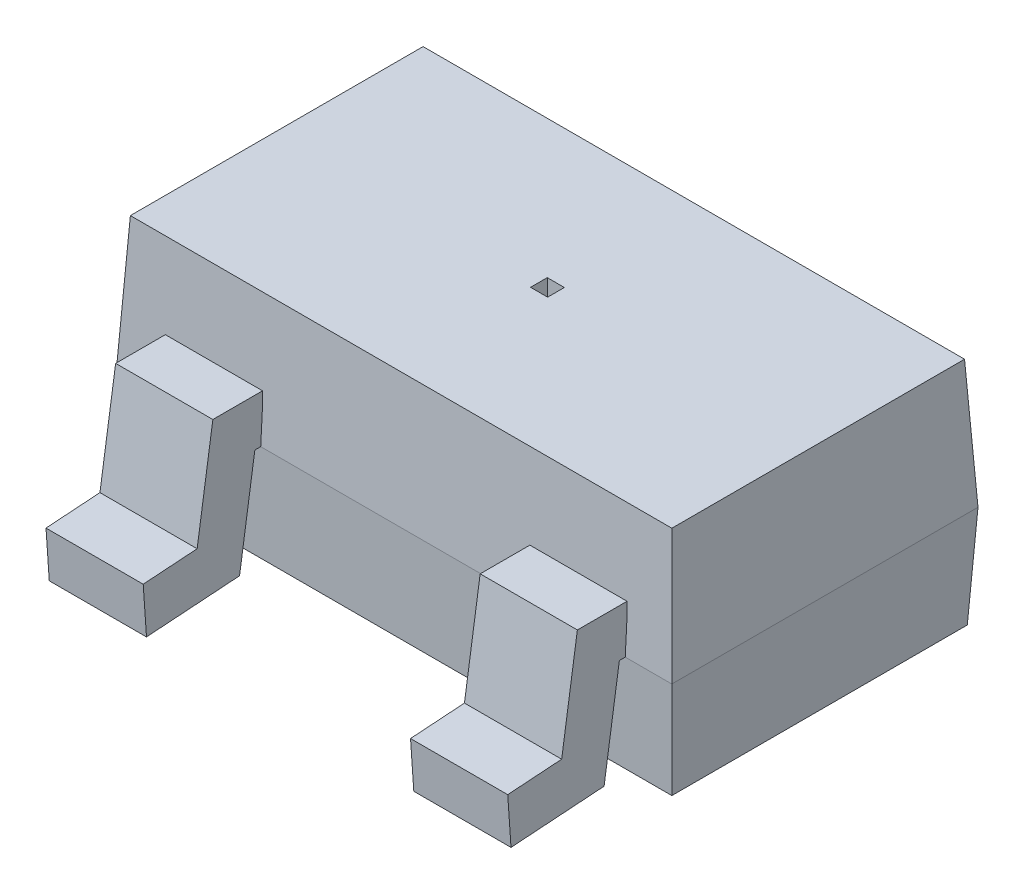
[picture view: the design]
ISO-10303-21;
HEADER;
FILE_DESCRIPTION(('STEP AP214'),'2;1');
FILE_NAME('part.step','',(''),(''),'','','');
FILE_SCHEMA(('AUTOMOTIVE_DESIGN { 1 0 10303 214 1 1 1 1 }'));
ENDSEC;
DATA;
#1=APPLICATION_CONTEXT('core data for automotive mechanical design processes');
#2=APPLICATION_PROTOCOL_DEFINITION('international standard','automotive_design',2000,#1);
#3=PRODUCT_CONTEXT('',#1,'mechanical');
#4=PRODUCT('Part','Part','',(#3));
#5=PRODUCT_RELATED_PRODUCT_CATEGORY('part','',(#4));
#6=PRODUCT_DEFINITION_FORMATION('','',#4);
#7=PRODUCT_DEFINITION_CONTEXT('part definition',#1,'design');
#8=PRODUCT_DEFINITION('design','',#6,#7);
#9=PRODUCT_DEFINITION_SHAPE('','',#8);
#10=(LENGTH_UNIT() NAMED_UNIT(*) SI_UNIT(.MILLI.,.METRE.));
#11=(NAMED_UNIT(*) PLANE_ANGLE_UNIT() SI_UNIT($,.RADIAN.));
#12=(NAMED_UNIT(*) SI_UNIT($,.STERADIAN.) SOLID_ANGLE_UNIT());
#13=UNCERTAINTY_MEASURE_WITH_UNIT(LENGTH_MEASURE(1.E-05),#10,'distance_accuracy_value','');
#14=(GEOMETRIC_REPRESENTATION_CONTEXT(3) GLOBAL_UNCERTAINTY_ASSIGNED_CONTEXT((#13)) GLOBAL_UNIT_ASSIGNED_CONTEXT((#10,
#11,#12)) REPRESENTATION_CONTEXT('',''));
#15=CARTESIAN_POINT('',(0.,0.,0.));
#16=DIRECTION('',(0.,0.,1.));
#17=DIRECTION('',(1.,0.,0.));
#18=AXIS2_PLACEMENT_3D('',#15,#16,#17);
#19=CARTESIAN_POINT('',(-1.45,0.,-0.8));
#20=DIRECTION('',(-0.998629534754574,-0.0523359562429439,0.));
#21=DIRECTION('',(0.0523359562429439,-0.998629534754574,0.));
#22=AXIS2_PLACEMENT_3D('',#19,#20,#21);
#23=PLANE('',#22);
#24=DIRECTION('',(0.,0.,1.));
#25=VECTOR('',#24,1.);
#26=CARTESIAN_POINT('',(-1.45,0.,-0.8));
#27=LINE('',#26,#25);
#28=CARTESIAN_POINT('',(-1.45,0.,-0.8));
#29=VERTEX_POINT('',#28);
#30=CARTESIAN_POINT('',(-1.45,0.,0.8));
#31=VERTEX_POINT('',#30);
#32=EDGE_CURVE('E491',#29,#31,#27,.T.);
#33=ORIENTED_EDGE('',*,*,#32,.F.);
#34=DIRECTION('',(-0.052264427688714,0.997264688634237,-0.052264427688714));
#35=VECTOR('',#34,1.);
#36=CARTESIAN_POINT('',(-1.45,0.,-0.8));
#37=LINE('',#36,#35);
#38=CARTESIAN_POINT('',(-1.42206665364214,-0.533,-0.772066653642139));
#39=VERTEX_POINT('',#38);
#40=EDGE_CURVE('E526',#39,#29,#37,.T.);
#41=ORIENTED_EDGE('',*,*,#40,.F.);
#42=DIRECTION('',(0.,0.,1.));
#43=VECTOR('',#42,1.);
#44=CARTESIAN_POINT('',(-1.42206665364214,-0.533,0.8));
#45=LINE('',#44,#43);
#46=CARTESIAN_POINT('',(-1.42206665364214,-0.533,0.772066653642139));
#47=VERTEX_POINT('',#46);
#48=EDGE_CURVE('E524',#39,#47,#45,.T.);
#49=ORIENTED_EDGE('',*,*,#48,.T.);
#50=DIRECTION('',(-0.052264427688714,0.997264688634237,0.052264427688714));
#51=VECTOR('',#50,1.);
#52=CARTESIAN_POINT('',(-1.44562948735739,-0.0833943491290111,0.795629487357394));
#53=LINE('',#52,#51);
#54=EDGE_CURVE('E531',#47,#31,#53,.T.);
#55=ORIENTED_EDGE('',*,*,#54,.T.);
#56=EDGE_LOOP('',(#33,#41,#49,#55));
#57=FACE_BOUND('',#56,.T.);
#58=ADVANCED_FACE('F38',(#57),#23,.T.);
#59=CARTESIAN_POINT('',(-1.45,0.,-0.8));
#60=DIRECTION('',(0.,-0.0523359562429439,-0.998629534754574));
#61=DIRECTION('',(0.,0.998629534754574,-0.0523359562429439));
#62=AXIS2_PLACEMENT_3D('',#59,#60,#61);
#63=PLANE('',#62);
#64=DIRECTION('',(-1.,0.,0.));
#65=VECTOR('',#64,1.);
#66=CARTESIAN_POINT('',(-1.45,0.,-0.8));
#67=LINE('',#66,#65);
#68=CARTESIAN_POINT('',(1.45,0.,-0.8));
#69=VERTEX_POINT('',#68);
#70=CARTESIAN_POINT('',(0.254,0.,-0.8));
#71=VERTEX_POINT('',#70);
#72=EDGE_CURVE('E521',#69,#71,#67,.T.);
#73=ORIENTED_EDGE('',*,*,#72,.F.);
#74=DIRECTION('',(0.052264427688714,0.997264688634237,-0.052264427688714));
#75=VECTOR('',#74,1.);
#76=CARTESIAN_POINT('',(1.45,0.,-0.8));
#77=LINE('',#76,#75);
#78=CARTESIAN_POINT('',(1.42206665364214,-0.533,-0.772066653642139));
#79=VERTEX_POINT('',#78);
#80=EDGE_CURVE('E530',#79,#69,#77,.T.);
#81=ORIENTED_EDGE('',*,*,#80,.F.);
#82=DIRECTION('',(-1.,0.,0.));
#83=VECTOR('',#82,1.);
#84=CARTESIAN_POINT('',(-1.45,-0.533,-0.772066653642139));
#85=LINE('',#84,#83);
#86=EDGE_CURVE('E534',#79,#39,#85,.T.);
#87=ORIENTED_EDGE('',*,*,#86,.T.);
#88=ORIENTED_EDGE('',*,*,#40,.T.);
#89=CARTESIAN_POINT('',(-0.254,0.,-0.8));
#90=VERTEX_POINT('',#89);
#91=EDGE_CURVE('E520',#90,#29,#67,.T.);
#92=ORIENTED_EDGE('',*,*,#91,.F.);
#93=EDGE_CURVE('E525',#71,#90,#67,.T.);
#94=ORIENTED_EDGE('',*,*,#93,.F.);
#95=EDGE_LOOP('',(#73,#81,#87,#88,#92,#94));
#96=FACE_BOUND('',#95,.T.);
#97=ADVANCED_FACE('F40',(#96),#63,.T.);
#98=CARTESIAN_POINT('',(1.45,0.,-0.8));
#99=DIRECTION('',(0.998629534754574,-0.0523359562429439,0.));
#100=DIRECTION('',(0.0523359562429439,0.998629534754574,0.));
#101=AXIS2_PLACEMENT_3D('',#98,#99,#100);
#102=PLANE('',#101);
#103=DIRECTION('',(0.,0.,-1.));
#104=VECTOR('',#103,1.);
#105=CARTESIAN_POINT('',(1.45,0.,-0.8));
#106=LINE('',#105,#104);
#107=CARTESIAN_POINT('',(1.45,0.,0.8));
#108=VERTEX_POINT('',#107);
#109=EDGE_CURVE('E514',#108,#69,#106,.T.);
#110=ORIENTED_EDGE('',*,*,#109,.F.);
#111=DIRECTION('',(0.052264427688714,0.997264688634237,0.052264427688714));
#112=VECTOR('',#111,1.);
#113=CARTESIAN_POINT('',(1.44207844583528,-0.151152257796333,0.792078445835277));
#114=LINE('',#113,#112);
#115=CARTESIAN_POINT('',(1.42206665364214,-0.533,0.772066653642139));
#116=VERTEX_POINT('',#115);
#117=EDGE_CURVE('E533',#116,#108,#114,.T.);
#118=ORIENTED_EDGE('',*,*,#117,.F.);
#119=DIRECTION('',(0.,0.,-1.));
#120=VECTOR('',#119,1.);
#121=CARTESIAN_POINT('',(1.42206665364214,-0.533,0.8));
#122=LINE('',#121,#120);
#123=EDGE_CURVE('E543',#116,#79,#122,.T.);
#124=ORIENTED_EDGE('',*,*,#123,.T.);
#125=ORIENTED_EDGE('',*,*,#80,.T.);
#126=EDGE_LOOP('',(#110,#118,#124,#125));
#127=FACE_BOUND('',#126,.T.);
#128=ADVANCED_FACE('F665',(#127),#102,.T.);
#129=CARTESIAN_POINT('',(-1.45,0.,0.8));
#130=DIRECTION('',(0.,-0.0523359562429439,0.998629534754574));
#131=DIRECTION('',(0.,-0.998629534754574,-0.0523359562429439));
#132=AXIS2_PLACEMENT_3D('',#129,#130,#131);
#133=PLANE('',#132);
#134=DIRECTION('',(1.,0.,0.));
#135=VECTOR('',#134,1.);
#136=CARTESIAN_POINT('',(-1.45,0.,0.8));
#137=LINE('',#136,#135);
#138=CARTESIAN_POINT('',(-1.2065,0.,0.8));
#139=VERTEX_POINT('',#138);
#140=EDGE_CURVE('E512',#31,#139,#137,.T.);
#141=ORIENTED_EDGE('',*,*,#140,.F.);
#142=ORIENTED_EDGE('',*,*,#54,.F.);
#143=DIRECTION('',(1.,0.,0.));
#144=VECTOR('',#143,1.);
#145=CARTESIAN_POINT('',(-1.45,-0.533,0.772066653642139));
#146=LINE('',#145,#144);
#147=EDGE_CURVE('E540',#47,#116,#146,.T.);
#148=ORIENTED_EDGE('',*,*,#147,.T.);
#149=ORIENTED_EDGE('',*,*,#117,.T.);
#150=CARTESIAN_POINT('',(1.2065,0.,0.8));
#151=VERTEX_POINT('',#150);
#152=EDGE_CURVE('E511',#151,#108,#137,.T.);
#153=ORIENTED_EDGE('',*,*,#152,.F.);
#154=CARTESIAN_POINT('',(0.6985,0.,0.8));
#155=VERTEX_POINT('',#154);
#156=EDGE_CURVE('E517',#155,#151,#137,.T.);
#157=ORIENTED_EDGE('',*,*,#156,.F.);
#158=CARTESIAN_POINT('',(-0.6985,0.,0.8));
#159=VERTEX_POINT('',#158);
#160=EDGE_CURVE('E516',#159,#155,#137,.T.);
#161=ORIENTED_EDGE('',*,*,#160,.F.);
#162=EDGE_CURVE('E515',#139,#159,#137,.T.);
#163=ORIENTED_EDGE('',*,*,#162,.F.);
#164=EDGE_LOOP('',(#141,#142,#148,#149,#153,#157,#161,#163));
#165=FACE_BOUND('',#164,.T.);
#166=ADVANCED_FACE('F672',(#165),#133,.T.);
#167=CARTESIAN_POINT('',(-1.45,-0.533,0.8));
#168=DIRECTION('',(0.,1.,0.));
#169=DIRECTION('',(0.,0.,1.));
#170=AXIS2_PLACEMENT_3D('',#167,#168,#169);
#171=PLANE('',#170);
#172=ORIENTED_EDGE('',*,*,#48,.F.);
#173=ORIENTED_EDGE('',*,*,#86,.F.);
#174=ORIENTED_EDGE('',*,*,#123,.F.);
#175=ORIENTED_EDGE('',*,*,#147,.F.);
#176=EDGE_LOOP('',(#172,#173,#174,#175));
#177=FACE_BOUND('',#176,.T.);
#178=ADVANCED_FACE('F670',(#177),#171,.F.);
#179=CARTESIAN_POINT('',(1.45,0.,-0.8));
#180=DIRECTION('',(0.,0.0523359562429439,-0.998629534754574));
#181=DIRECTION('',(0.,0.998629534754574,0.0523359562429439));
#182=AXIS2_PLACEMENT_3D('',#179,#180,#181);
#183=PLANE('',#182);
#184=ORIENTED_EDGE('',*,*,#72,.T.);
#185=DIRECTION('',(0.,-0.998629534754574,-0.0523359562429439));
#186=VECTOR('',#185,1.);
#187=CARTESIAN_POINT('',(0.254,0.,-0.8));
#188=LINE('',#187,#186);
#189=CARTESIAN_POINT('',(0.254,0.18203300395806,-0.790460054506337));
#190=VERTEX_POINT('',#189);
#191=EDGE_CURVE('E553',#71,#190,#188,.F.);
#192=ORIENTED_EDGE('',*,*,#191,.T.);
#193=DIRECTION('',(-1.,0.,0.));
#194=VECTOR('',#193,1.);
#195=CARTESIAN_POINT('',(1.45,0.18203300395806,-0.790460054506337));
#196=LINE('',#195,#194);
#197=CARTESIAN_POINT('',(-0.254,0.182033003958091,-0.790460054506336));
#198=VERTEX_POINT('',#197);
#199=EDGE_CURVE('E550',#198,#190,#196,.F.);
#200=ORIENTED_EDGE('',*,*,#199,.F.);
#201=DIRECTION('',(0.,-0.998629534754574,-0.0523359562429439));
#202=VECTOR('',#201,1.);
#203=CARTESIAN_POINT('',(-0.254,0.,-0.8));
#204=LINE('',#203,#202);
#205=EDGE_CURVE('E529',#90,#198,#204,.F.);
#206=ORIENTED_EDGE('',*,*,#205,.F.);
#207=ORIENTED_EDGE('',*,*,#91,.T.);
#208=DIRECTION('',(-0.052264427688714,-0.997264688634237,-0.052264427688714));
#209=VECTOR('',#208,1.);
#210=CARTESIAN_POINT('',(-1.45,0.,-0.8));
#211=LINE('',#210,#209);
#212=CARTESIAN_POINT('',(-1.41488678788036,0.67,-0.764886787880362));
#213=VERTEX_POINT('',#212);
#214=EDGE_CURVE('E488',#213,#29,#211,.T.);
#215=ORIENTED_EDGE('',*,*,#214,.F.);
#216=DIRECTION('',(1.,0.,0.));
#217=VECTOR('',#216,1.);
#218=CARTESIAN_POINT('',(1.45,0.67,-0.764886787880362));
#219=LINE('',#218,#217);
#220=CARTESIAN_POINT('',(1.41488678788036,0.67,-0.764886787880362));
#221=VERTEX_POINT('',#220);
#222=EDGE_CURVE('E487',#221,#213,#219,.F.);
#223=ORIENTED_EDGE('',*,*,#222,.F.);
#224=DIRECTION('',(0.052264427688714,-0.997264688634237,-0.052264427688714));
#225=VECTOR('',#224,1.);
#226=CARTESIAN_POINT('',(1.45,0.,-0.8));
#227=LINE('',#226,#225);
#228=EDGE_CURVE('E493',#221,#69,#227,.T.);
#229=ORIENTED_EDGE('',*,*,#228,.T.);
#230=EDGE_LOOP('',(#184,#192,#200,#206,#207,#215,#223,#229));
#231=FACE_BOUND('',#230,.T.);
#232=ADVANCED_FACE('F777',(#231),#183,.T.);
#233=CARTESIAN_POINT('',(-1.45,0.,-0.8));
#234=DIRECTION('',(-0.998629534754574,0.0523359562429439,0.));
#235=DIRECTION('',(-0.0523359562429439,-0.998629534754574,0.));
#236=AXIS2_PLACEMENT_3D('',#233,#234,#235);
#237=PLANE('',#236);
#238=ORIENTED_EDGE('',*,*,#32,.T.);
#239=DIRECTION('',(-0.052264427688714,-0.997264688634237,0.052264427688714));
#240=VECTOR('',#239,1.);
#241=CARTESIAN_POINT('',(-1.45,0.,0.8));
#242=LINE('',#241,#240);
#243=CARTESIAN_POINT('',(-1.41488678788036,0.67,0.764886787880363));
#244=VERTEX_POINT('',#243);
#245=EDGE_CURVE('E492',#244,#31,#242,.T.);
#246=ORIENTED_EDGE('',*,*,#245,.F.);
#247=DIRECTION('',(0.,0.,-1.));
#248=VECTOR('',#247,1.);
#249=CARTESIAN_POINT('',(-1.41488678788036,0.67,-0.8));
#250=LINE('',#249,#248);
#251=EDGE_CURVE('E504',#213,#244,#250,.F.);
#252=ORIENTED_EDGE('',*,*,#251,.F.);
#253=ORIENTED_EDGE('',*,*,#214,.T.);
#254=EDGE_LOOP('',(#238,#246,#252,#253));
#255=FACE_BOUND('',#254,.T.);
#256=ADVANCED_FACE('F692',(#255),#237,.T.);
#257=CARTESIAN_POINT('',(-1.45,0.,0.8));
#258=DIRECTION('',(0.,0.0523359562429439,0.998629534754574));
#259=DIRECTION('',(0.,-0.998629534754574,0.0523359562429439));
#260=AXIS2_PLACEMENT_3D('',#257,#258,#259);
#261=PLANE('',#260);
#262=ORIENTED_EDGE('',*,*,#140,.T.);
#263=DIRECTION('',(0.,-0.998629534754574,0.0523359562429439));
#264=VECTOR('',#263,1.);
#265=CARTESIAN_POINT('',(-1.2065,0.,0.8));
#266=LINE('',#265,#264);
#267=CARTESIAN_POINT('',(-1.2065,0.182033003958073,0.790460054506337));
#268=VERTEX_POINT('',#267);
#269=EDGE_CURVE('E11',#139,#268,#266,.F.);
#270=ORIENTED_EDGE('',*,*,#269,.T.);
#271=DIRECTION('',(-1.,0.,0.));
#272=VECTOR('',#271,1.);
#273=CARTESIAN_POINT('',(-1.45,0.182033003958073,0.790460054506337));
#274=LINE('',#273,#272);
#275=CARTESIAN_POINT('',(-0.6985,0.182033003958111,0.790460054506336));
#276=VERTEX_POINT('',#275);
#277=EDGE_CURVE('E46',#268,#276,#274,.F.);
#278=ORIENTED_EDGE('',*,*,#277,.T.);
#279=DIRECTION('',(0.,-0.998629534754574,0.0523359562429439));
#280=VECTOR('',#279,1.);
#281=CARTESIAN_POINT('',(-0.6985,0.,0.8));
#282=LINE('',#281,#280);
#283=EDGE_CURVE('E563',#159,#276,#282,.F.);
#284=ORIENTED_EDGE('',*,*,#283,.F.);
#285=ORIENTED_EDGE('',*,*,#160,.T.);
#286=DIRECTION('',(0.,0.998629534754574,-0.0523359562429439));
#287=VECTOR('',#286,1.);
#288=CARTESIAN_POINT('',(0.6985,0.,0.8));
#289=LINE('',#288,#287);
#290=CARTESIAN_POINT('',(0.6985,0.182033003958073,0.790460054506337));
#291=VERTEX_POINT('',#290);
#292=EDGE_CURVE('E555',#291,#155,#289,.F.);
#293=ORIENTED_EDGE('',*,*,#292,.F.);
#294=DIRECTION('',(1.,0.,0.));
#295=VECTOR('',#294,1.);
#296=CARTESIAN_POINT('',(-1.45,0.182033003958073,0.790460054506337));
#297=LINE('',#296,#295);
#298=CARTESIAN_POINT('',(1.2065,0.182033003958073,0.790460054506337));
#299=VERTEX_POINT('',#298);
#300=EDGE_CURVE('E558',#299,#291,#297,.F.);
#301=ORIENTED_EDGE('',*,*,#300,.F.);
#302=DIRECTION('',(0.,0.998629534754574,-0.0523359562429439));
#303=VECTOR('',#302,1.);
#304=CARTESIAN_POINT('',(1.2065,0.,0.8));
#305=LINE('',#304,#303);
#306=EDGE_CURVE('E561',#299,#151,#305,.F.);
#307=ORIENTED_EDGE('',*,*,#306,.T.);
#308=ORIENTED_EDGE('',*,*,#152,.T.);
#309=DIRECTION('',(0.052264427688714,-0.997264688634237,0.052264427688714));
#310=VECTOR('',#309,1.);
#311=CARTESIAN_POINT('',(1.45,0.,0.8));
#312=LINE('',#311,#310);
#313=CARTESIAN_POINT('',(1.41488678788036,0.67,0.764886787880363));
#314=VERTEX_POINT('',#313);
#315=EDGE_CURVE('E496',#314,#108,#312,.T.);
#316=ORIENTED_EDGE('',*,*,#315,.F.);
#317=DIRECTION('',(-1.,0.,0.));
#318=VECTOR('',#317,1.);
#319=CARTESIAN_POINT('',(-1.45,0.67,0.764886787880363));
#320=LINE('',#319,#318);
#321=EDGE_CURVE('E506',#244,#314,#320,.F.);
#322=ORIENTED_EDGE('',*,*,#321,.F.);
#323=ORIENTED_EDGE('',*,*,#245,.T.);
#324=EDGE_LOOP('',(#262,#270,#278,#284,#285,#293,#301,#307,#308,#316,#322,#323));
#325=FACE_BOUND('',#324,.T.);
#326=ADVANCED_FACE('F565',(#325),#261,.T.);
#327=CARTESIAN_POINT('',(1.45,0.,0.8));
#328=DIRECTION('',(0.998629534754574,0.0523359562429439,0.));
#329=DIRECTION('',(-0.0523359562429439,0.998629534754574,0.));
#330=AXIS2_PLACEMENT_3D('',#327,#328,#329);
#331=PLANE('',#330);
#332=ORIENTED_EDGE('',*,*,#109,.T.);
#333=ORIENTED_EDGE('',*,*,#228,.F.);
#334=DIRECTION('',(0.,0.,1.));
#335=VECTOR('',#334,1.);
#336=CARTESIAN_POINT('',(1.41488678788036,0.67,0.8));
#337=LINE('',#336,#335);
#338=EDGE_CURVE('E497',#314,#221,#337,.F.);
#339=ORIENTED_EDGE('',*,*,#338,.F.);
#340=ORIENTED_EDGE('',*,*,#315,.T.);
#341=EDGE_LOOP('',(#332,#333,#339,#340));
#342=FACE_BOUND('',#341,.T.);
#343=ADVANCED_FACE('F684',(#342),#331,.T.);
#344=CARTESIAN_POINT('',(-1.45,0.67,-0.8));
#345=DIRECTION('',(0.,1.,0.));
#346=DIRECTION('',(0.,0.,1.));
#347=AXIS2_PLACEMENT_3D('',#344,#345,#346);
#348=PLANE('',#347);
#349=DIRECTION('',(0.,0.,1.));
#350=VECTOR('',#349,1.);
#351=CARTESIAN_POINT('',(-0.0446511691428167,0.67,-0.0437209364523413));
#352=LINE('',#351,#350);
#353=CARTESIAN_POINT('',(-0.0446511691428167,0.67,-0.0437209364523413));
#354=VERTEX_POINT('',#353);
#355=CARTESIAN_POINT('',(-0.0446511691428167,0.67,0.0437209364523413));
#356=VERTEX_POINT('',#355);
#357=EDGE_CURVE('E53',#354,#356,#352,.T.);
#358=ORIENTED_EDGE('',*,*,#357,.F.);
#359=DIRECTION('',(-1.,0.,0.));
#360=VECTOR('',#359,1.);
#361=CARTESIAN_POINT('',(-0.0446511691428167,0.67,-0.0437209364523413));
#362=LINE('',#361,#360);
#363=CARTESIAN_POINT('',(0.0446511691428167,0.67,-0.0437209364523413));
#364=VERTEX_POINT('',#363);
#365=EDGE_CURVE('E296',#364,#354,#362,.T.);
#366=ORIENTED_EDGE('',*,*,#365,.F.);
#367=DIRECTION('',(0.,0.,-1.));
#368=VECTOR('',#367,1.);
#369=CARTESIAN_POINT('',(0.0446511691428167,0.67,-0.0437209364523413));
#370=LINE('',#369,#368);
#371=CARTESIAN_POINT('',(0.0446511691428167,0.67,0.0437209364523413));
#372=VERTEX_POINT('',#371);
#373=EDGE_CURVE('E299',#372,#364,#370,.T.);
#374=ORIENTED_EDGE('',*,*,#373,.F.);
#375=DIRECTION('',(1.,0.,0.));
#376=VECTOR('',#375,1.);
#377=CARTESIAN_POINT('',(-0.0446511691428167,0.67,0.0437209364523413));
#378=LINE('',#377,#376);
#379=EDGE_CURVE('E305',#356,#372,#378,.T.);
#380=ORIENTED_EDGE('',*,*,#379,.F.);
#381=EDGE_LOOP('',(#358,#366,#374,#380));
#382=FACE_BOUND('',#381,.T.);
#383=ORIENTED_EDGE('',*,*,#222,.T.);
#384=ORIENTED_EDGE('',*,*,#251,.T.);
#385=ORIENTED_EDGE('',*,*,#321,.T.);
#386=ORIENTED_EDGE('',*,*,#338,.T.);
#387=EDGE_LOOP('',(#383,#384,#385,#386));
#388=FACE_BOUND('',#387,.T.);
#389=ADVANCED_FACE('F688',(#382,#388),#348,.T.);
#390=CARTESIAN_POINT('',(0.254,0.248,-0.790460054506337));
#391=DIRECTION('',(0.,0.,-1.));
#392=DIRECTION('',(-1.,0.,0.));
#393=AXIS2_PLACEMENT_3D('',#390,#391,#392);
#394=PLANE('',#393);
#395=DIRECTION('',(0.,-1.,0.));
#396=VECTOR('',#395,1.);
#397=CARTESIAN_POINT('',(-0.254,0.248,-0.790460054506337));
#398=LINE('',#397,#396);
#399=CARTESIAN_POINT('',(-0.254,0.248,-0.790460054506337));
#400=VERTEX_POINT('',#399);
#401=EDGE_CURVE('E432',#400,#198,#398,.T.);
#402=ORIENTED_EDGE('',*,*,#401,.T.);
#403=ORIENTED_EDGE('',*,*,#199,.T.);
#404=DIRECTION('',(0.,-1.,0.));
#405=VECTOR('',#404,1.);
#406=CARTESIAN_POINT('',(0.254,0.248,-0.790460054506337));
#407=LINE('',#406,#405);
#408=CARTESIAN_POINT('',(0.254,0.248,-0.790460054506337));
#409=VERTEX_POINT('',#408);
#410=EDGE_CURVE('E433',#409,#190,#407,.T.);
#411=ORIENTED_EDGE('',*,*,#410,.F.);
#412=DIRECTION('',(-1.,0.,0.));
#413=VECTOR('',#412,1.);
#414=CARTESIAN_POINT('',(0.254,0.248,-0.790460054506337));
#415=LINE('',#414,#413);
#416=EDGE_CURVE('E451',#409,#400,#415,.T.);
#417=ORIENTED_EDGE('',*,*,#416,.T.);
#418=EDGE_LOOP('',(#402,#403,#411,#417));
#419=FACE_BOUND('',#418,.T.);
#420=ADVANCED_FACE('F769',(#419),#394,.F.);
#421=CARTESIAN_POINT('',(0.254,0.,-0.790460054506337));
#422=DIRECTION('',(0.,1.,0.));
#423=DIRECTION('',(0.,0.,1.));
#424=AXIS2_PLACEMENT_3D('',#421,#422,#423);
#425=PLANE('',#424);
#426=DIRECTION('',(0.,0.,-1.));
#427=VECTOR('',#426,1.);
#428=CARTESIAN_POINT('',(0.254,0.,-0.790460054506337));
#429=LINE('',#428,#427);
#430=CARTESIAN_POINT('',(0.254,0.,-0.830732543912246));
#431=VERTEX_POINT('',#430);
#432=EDGE_CURVE('E436',#71,#431,#429,.T.);
#433=ORIENTED_EDGE('',*,*,#432,.F.);
#434=ORIENTED_EDGE('',*,*,#93,.T.);
#435=DIRECTION('',(0.,0.,-1.));
#436=VECTOR('',#435,1.);
#437=CARTESIAN_POINT('',(-0.254,0.,-0.790460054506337));
#438=LINE('',#437,#436);
#439=CARTESIAN_POINT('',(-0.254,0.,-0.830732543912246));
#440=VERTEX_POINT('',#439);
#441=EDGE_CURVE('E454',#90,#440,#438,.T.);
#442=ORIENTED_EDGE('',*,*,#441,.T.);
#443=DIRECTION('',(-1.,0.,0.));
#444=VECTOR('',#443,1.);
#445=CARTESIAN_POINT('',(0.254,0.,-0.830732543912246));
#446=LINE('',#445,#444);
#447=EDGE_CURVE('E484',#431,#440,#446,.T.);
#448=ORIENTED_EDGE('',*,*,#447,.F.);
#449=EDGE_LOOP('',(#433,#434,#442,#448));
#450=FACE_BOUND('',#449,.T.);
#451=ADVANCED_FACE('F765',(#450),#425,.F.);
#452=CARTESIAN_POINT('',(0.254,0.,-0.790460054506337));
#453=DIRECTION('',(1.,0.,0.));
#454=DIRECTION('',(0.,0.,-1.));
#455=AXIS2_PLACEMENT_3D('',#452,#453,#454);
#456=PLANE('',#455);
#457=ORIENTED_EDGE('',*,*,#191,.F.);
#458=ORIENTED_EDGE('',*,*,#432,.T.);
#459=DIRECTION('',(0.,-0.98880509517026,-0.149212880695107));
#460=VECTOR('',#459,1.);
#461=CARTESIAN_POINT('',(0.254,0.,-0.830732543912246));
#462=LINE('',#461,#460);
#463=CARTESIAN_POINT('',(0.254,-0.529179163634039,-0.910586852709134));
#464=VERTEX_POINT('',#463);
#465=EDGE_CURVE('E439',#431,#464,#462,.T.);
#466=ORIENTED_EDGE('',*,*,#465,.T.);
#467=DIRECTION('',(0.,-0.0690684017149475,-0.997611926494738));
#468=VECTOR('',#467,1.);
#469=CARTESIAN_POINT('',(0.254,-0.529179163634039,-0.910586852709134));
#470=LINE('',#469,#468);
#471=CARTESIAN_POINT('',(0.254,-0.562855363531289,-1.397));
#472=VERTEX_POINT('',#471);
#473=EDGE_CURVE('E441',#464,#472,#470,.T.);
#474=ORIENTED_EDGE('',*,*,#473,.T.);
#475=DIRECTION('',(0.,0.997611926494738,-0.0690684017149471));
#476=VECTOR('',#475,1.);
#477=CARTESIAN_POINT('',(0.254,-0.315447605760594,-1.41412896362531));
#478=LINE('',#477,#476);
#479=CARTESIAN_POINT('',(0.254,-0.315447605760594,-1.41412896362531));
#480=VERTEX_POINT('',#479);
#481=EDGE_CURVE('E443',#472,#480,#478,.T.);
#482=ORIENTED_EDGE('',*,*,#481,.T.);
#483=DIRECTION('',(0.,0.0690684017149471,0.997611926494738));
#484=VECTOR('',#483,1.);
#485=CARTESIAN_POINT('',(0.254,-0.295933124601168,-1.13226520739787));
#486=LINE('',#485,#484);
#487=CARTESIAN_POINT('',(0.254,-0.295933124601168,-1.13226520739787));
#488=VERTEX_POINT('',#487);
#489=EDGE_CURVE('E445',#480,#488,#486,.T.);
#490=ORIENTED_EDGE('',*,*,#489,.T.);
#491=DIRECTION('',(0.,0.98880509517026,0.149212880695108));
#492=VECTOR('',#491,1.);
#493=CARTESIAN_POINT('',(0.254,0.248,-1.05018449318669));
#494=LINE('',#493,#492);
#495=CARTESIAN_POINT('',(0.254,0.248,-1.05018449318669));
#496=VERTEX_POINT('',#495);
#497=EDGE_CURVE('E447',#488,#496,#494,.T.);
#498=ORIENTED_EDGE('',*,*,#497,.T.);
#499=DIRECTION('',(0.,0.,1.));
#500=VECTOR('',#499,1.);
#501=CARTESIAN_POINT('',(0.254,0.248,-0.790460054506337));
#502=LINE('',#501,#500);
#503=EDGE_CURVE('E449',#496,#409,#502,.T.);
#504=ORIENTED_EDGE('',*,*,#503,.T.);
#505=ORIENTED_EDGE('',*,*,#410,.T.);
#506=EDGE_LOOP('',(#457,#458,#466,#474,#482,#490,#498,#504,#505));
#507=FACE_BOUND('',#506,.T.);
#508=ADVANCED_FACE('F768',(#507),#456,.T.);
#509=CARTESIAN_POINT('',(-0.254,0.,-0.790460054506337));
#510=DIRECTION('',(1.,0.,0.));
#511=DIRECTION('',(0.,0.,-1.));
#512=AXIS2_PLACEMENT_3D('',#509,#510,#511);
#513=PLANE('',#512);
#514=ORIENTED_EDGE('',*,*,#441,.F.);
#515=ORIENTED_EDGE('',*,*,#205,.T.);
#516=ORIENTED_EDGE('',*,*,#401,.F.);
#517=DIRECTION('',(0.,0.,1.));
#518=VECTOR('',#517,1.);
#519=CARTESIAN_POINT('',(-0.254,0.248,-0.790460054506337));
#520=LINE('',#519,#518);
#521=CARTESIAN_POINT('',(-0.254,0.248,-1.05018449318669));
#522=VERTEX_POINT('',#521);
#523=EDGE_CURVE('E437',#522,#400,#520,.T.);
#524=ORIENTED_EDGE('',*,*,#523,.F.);
#525=DIRECTION('',(0.,0.98880509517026,0.149212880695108));
#526=VECTOR('',#525,1.);
#527=CARTESIAN_POINT('',(-0.254,0.248,-1.05018449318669));
#528=LINE('',#527,#526);
#529=CARTESIAN_POINT('',(-0.254,-0.295933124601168,-1.13226520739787));
#530=VERTEX_POINT('',#529);
#531=EDGE_CURVE('E464',#530,#522,#528,.T.);
#532=ORIENTED_EDGE('',*,*,#531,.F.);
#533=DIRECTION('',(0.,0.0690684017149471,0.997611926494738));
#534=VECTOR('',#533,1.);
#535=CARTESIAN_POINT('',(-0.254,-0.295933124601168,-1.13226520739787));
#536=LINE('',#535,#534);
#537=CARTESIAN_POINT('',(-0.254,-0.315447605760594,-1.41412896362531));
#538=VERTEX_POINT('',#537);
#539=EDGE_CURVE('E462',#538,#530,#536,.T.);
#540=ORIENTED_EDGE('',*,*,#539,.F.);
#541=DIRECTION('',(0.,0.997611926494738,-0.0690684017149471));
#542=VECTOR('',#541,1.);
#543=CARTESIAN_POINT('',(-0.254,-0.315447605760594,-1.41412896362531));
#544=LINE('',#543,#542);
#545=CARTESIAN_POINT('',(-0.254,-0.562855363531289,-1.397));
#546=VERTEX_POINT('',#545);
#547=EDGE_CURVE('E460',#546,#538,#544,.T.);
#548=ORIENTED_EDGE('',*,*,#547,.F.);
#549=DIRECTION('',(0.,-0.0690684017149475,-0.997611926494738));
#550=VECTOR('',#549,1.);
#551=CARTESIAN_POINT('',(-0.254,-0.529179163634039,-0.910586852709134));
#552=LINE('',#551,#550);
#553=CARTESIAN_POINT('',(-0.254,-0.529179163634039,-0.910586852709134));
#554=VERTEX_POINT('',#553);
#555=EDGE_CURVE('E458',#554,#546,#552,.T.);
#556=ORIENTED_EDGE('',*,*,#555,.F.);
#557=DIRECTION('',(0.,-0.98880509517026,-0.149212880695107));
#558=VECTOR('',#557,1.);
#559=CARTESIAN_POINT('',(-0.254,0.,-0.830732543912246));
#560=LINE('',#559,#558);
#561=EDGE_CURVE('E456',#440,#554,#560,.T.);
#562=ORIENTED_EDGE('',*,*,#561,.F.);
#563=EDGE_LOOP('',(#514,#515,#516,#524,#532,#540,#548,#556,#562));
#564=FACE_BOUND('',#563,.T.);
#565=ADVANCED_FACE('F747',(#564),#513,.F.);
#566=CARTESIAN_POINT('',(0.254,0.,-0.830732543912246));
#567=DIRECTION('',(0.,0.149212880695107,-0.98880509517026));
#568=DIRECTION('',(0.,0.98880509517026,0.149212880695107));
#569=AXIS2_PLACEMENT_3D('',#566,#567,#568);
#570=PLANE('',#569);
#571=ORIENTED_EDGE('',*,*,#561,.T.);
#572=DIRECTION('',(-1.,0.,0.));
#573=VECTOR('',#572,1.);
#574=CARTESIAN_POINT('',(0.254,-0.529179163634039,-0.910586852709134));
#575=LINE('',#574,#573);
#576=EDGE_CURVE('E481',#464,#554,#575,.T.);
#577=ORIENTED_EDGE('',*,*,#576,.F.);
#578=ORIENTED_EDGE('',*,*,#465,.F.);
#579=ORIENTED_EDGE('',*,*,#447,.T.);
#580=EDGE_LOOP('',(#571,#577,#578,#579));
#581=FACE_BOUND('',#580,.T.);
#582=ADVANCED_FACE('F760',(#581),#570,.F.);
#583=CARTESIAN_POINT('',(0.254,-0.529179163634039,-0.910586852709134));
#584=DIRECTION('',(0.,0.997611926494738,-0.0690684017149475));
#585=DIRECTION('',(0.,0.0690684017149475,0.997611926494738));
#586=AXIS2_PLACEMENT_3D('',#583,#584,#585);
#587=PLANE('',#586);
#588=ORIENTED_EDGE('',*,*,#555,.T.);
#589=DIRECTION('',(-1.,0.,0.));
#590=VECTOR('',#589,1.);
#591=CARTESIAN_POINT('',(0.254,-0.562855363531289,-1.397));
#592=LINE('',#591,#590);
#593=EDGE_CURVE('E478',#472,#546,#592,.T.);
#594=ORIENTED_EDGE('',*,*,#593,.F.);
#595=ORIENTED_EDGE('',*,*,#473,.F.);
#596=ORIENTED_EDGE('',*,*,#576,.T.);
#597=EDGE_LOOP('',(#588,#594,#595,#596));
#598=FACE_BOUND('',#597,.T.);
#599=ADVANCED_FACE('F756',(#598),#587,.F.);
#600=CARTESIAN_POINT('',(0.254,-0.315447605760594,-1.41412896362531));
#601=DIRECTION('',(0.,0.0690684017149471,0.997611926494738));
#602=DIRECTION('',(0.,-0.997611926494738,0.0690684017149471));
#603=AXIS2_PLACEMENT_3D('',#600,#601,#602);
#604=PLANE('',#603);
#605=ORIENTED_EDGE('',*,*,#547,.T.);
#606=DIRECTION('',(-1.,0.,0.));
#607=VECTOR('',#606,1.);
#608=CARTESIAN_POINT('',(0.254,-0.315447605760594,-1.41412896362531));
#609=LINE('',#608,#607);
#610=EDGE_CURVE('E475',#480,#538,#609,.T.);
#611=ORIENTED_EDGE('',*,*,#610,.F.);
#612=ORIENTED_EDGE('',*,*,#481,.F.);
#613=ORIENTED_EDGE('',*,*,#593,.T.);
#614=EDGE_LOOP('',(#605,#611,#612,#613));
#615=FACE_BOUND('',#614,.T.);
#616=ADVANCED_FACE('F752',(#615),#604,.F.);
#617=CARTESIAN_POINT('',(0.254,-0.295933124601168,-1.13226520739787));
#618=DIRECTION('',(0.,-0.997611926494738,0.0690684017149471));
#619=DIRECTION('',(0.,-0.0690684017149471,-0.997611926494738));
#620=AXIS2_PLACEMENT_3D('',#617,#618,#619);
#621=PLANE('',#620);
#622=ORIENTED_EDGE('',*,*,#539,.T.);
#623=DIRECTION('',(-1.,0.,0.));
#624=VECTOR('',#623,1.);
#625=CARTESIAN_POINT('',(0.254,-0.295933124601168,-1.13226520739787));
#626=LINE('',#625,#624);
#627=EDGE_CURVE('E472',#488,#530,#626,.T.);
#628=ORIENTED_EDGE('',*,*,#627,.F.);
#629=ORIENTED_EDGE('',*,*,#489,.F.);
#630=ORIENTED_EDGE('',*,*,#610,.T.);
#631=EDGE_LOOP('',(#622,#628,#629,#630));
#632=FACE_BOUND('',#631,.T.);
#633=ADVANCED_FACE('F743',(#632),#621,.F.);
#634=CARTESIAN_POINT('',(0.254,0.248,-1.05018449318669));
#635=DIRECTION('',(0.,-0.149212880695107,0.98880509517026));
#636=DIRECTION('',(0.,-0.98880509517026,-0.149212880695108));
#637=AXIS2_PLACEMENT_3D('',#634,#635,#636);
#638=PLANE('',#637);
#639=ORIENTED_EDGE('',*,*,#531,.T.);
#640=DIRECTION('',(-1.,0.,0.));
#641=VECTOR('',#640,1.);
#642=CARTESIAN_POINT('',(0.254,0.248,-1.05018449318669));
#643=LINE('',#642,#641);
#644=EDGE_CURVE('E469',#496,#522,#643,.T.);
#645=ORIENTED_EDGE('',*,*,#644,.F.);
#646=ORIENTED_EDGE('',*,*,#497,.F.);
#647=ORIENTED_EDGE('',*,*,#627,.T.);
#648=EDGE_LOOP('',(#639,#645,#646,#647));
#649=FACE_BOUND('',#648,.T.);
#650=ADVANCED_FACE('F737',(#649),#638,.F.);
#651=CARTESIAN_POINT('',(0.254,0.248,-0.790460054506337));
#652=DIRECTION('',(0.,-1.,0.));
#653=DIRECTION('',(0.,0.,-1.));
#654=AXIS2_PLACEMENT_3D('',#651,#652,#653);
#655=PLANE('',#654);
#656=ORIENTED_EDGE('',*,*,#523,.T.);
#657=ORIENTED_EDGE('',*,*,#416,.F.);
#658=ORIENTED_EDGE('',*,*,#503,.F.);
#659=ORIENTED_EDGE('',*,*,#644,.T.);
#660=EDGE_LOOP('',(#656,#657,#658,#659));
#661=FACE_BOUND('',#660,.T.);
#662=ADVANCED_FACE('F733',(#661),#655,.F.);
#663=CARTESIAN_POINT('',(1.2065,0.,0.790460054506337));
#664=DIRECTION('',(0.,1.,0.));
#665=DIRECTION('',(0.,0.,1.));
#666=AXIS2_PLACEMENT_3D('',#663,#664,#665);
#667=PLANE('',#666);
#668=DIRECTION('',(0.,0.,-1.));
#669=VECTOR('',#668,1.);
#670=CARTESIAN_POINT('',(0.6985,0.,0.790460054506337));
#671=LINE('',#670,#669);
#672=CARTESIAN_POINT('',(0.6985,0.,0.830732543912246));
#673=VERTEX_POINT('',#672);
#674=EDGE_CURVE('E408',#673,#155,#671,.T.);
#675=ORIENTED_EDGE('',*,*,#674,.T.);
#676=ORIENTED_EDGE('',*,*,#156,.T.);
#677=DIRECTION('',(0.,0.,-1.));
#678=VECTOR('',#677,1.);
#679=CARTESIAN_POINT('',(1.2065,0.,0.790460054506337));
#680=LINE('',#679,#678);
#681=CARTESIAN_POINT('',(1.2065,0.,0.830732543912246));
#682=VERTEX_POINT('',#681);
#683=EDGE_CURVE('E390',#682,#151,#680,.T.);
#684=ORIENTED_EDGE('',*,*,#683,.F.);
#685=DIRECTION('',(-1.,0.,0.));
#686=VECTOR('',#685,1.);
#687=CARTESIAN_POINT('',(1.2065,0.,0.830732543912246));
#688=LINE('',#687,#686);
#689=EDGE_CURVE('E414',#682,#673,#688,.T.);
#690=ORIENTED_EDGE('',*,*,#689,.T.);
#691=EDGE_LOOP('',(#675,#676,#684,#690));
#692=FACE_BOUND('',#691,.T.);
#693=ADVANCED_FACE('F611',(#692),#667,.F.);
#694=CARTESIAN_POINT('',(1.2065,0.248,0.790460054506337));
#695=DIRECTION('',(0.,0.,1.));
#696=DIRECTION('',(1.,0.,0.));
#697=AXIS2_PLACEMENT_3D('',#694,#695,#696);
#698=PLANE('',#697);
#699=DIRECTION('',(0.,1.,0.));
#700=VECTOR('',#699,1.);
#701=CARTESIAN_POINT('',(1.2065,0.248,0.790460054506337));
#702=LINE('',#701,#700);
#703=CARTESIAN_POINT('',(1.2065,0.248,0.790460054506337));
#704=VERTEX_POINT('',#703);
#705=EDGE_CURVE('E393',#299,#704,#702,.T.);
#706=ORIENTED_EDGE('',*,*,#705,.F.);
#707=ORIENTED_EDGE('',*,*,#300,.T.);
#708=DIRECTION('',(0.,1.,0.));
#709=VECTOR('',#708,1.);
#710=CARTESIAN_POINT('',(0.6985,0.248,0.790460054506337));
#711=LINE('',#710,#709);
#712=CARTESIAN_POINT('',(0.6985,0.248,0.790460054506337));
#713=VERTEX_POINT('',#712);
#714=EDGE_CURVE('E380',#291,#713,#711,.T.);
#715=ORIENTED_EDGE('',*,*,#714,.T.);
#716=DIRECTION('',(-1.,0.,0.));
#717=VECTOR('',#716,1.);
#718=CARTESIAN_POINT('',(1.2065,0.248,0.790460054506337));
#719=LINE('',#718,#717);
#720=EDGE_CURVE('E395',#704,#713,#719,.T.);
#721=ORIENTED_EDGE('',*,*,#720,.F.);
#722=EDGE_LOOP('',(#706,#707,#715,#721));
#723=FACE_BOUND('',#722,.T.);
#724=ADVANCED_FACE('F630',(#723),#698,.F.);
#725=CARTESIAN_POINT('',(1.2065,0.248,0.790460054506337));
#726=DIRECTION('',(1.,0.,0.));
#727=DIRECTION('',(0.,0.,-1.));
#728=AXIS2_PLACEMENT_3D('',#725,#726,#727);
#729=PLANE('',#728);
#730=ORIENTED_EDGE('',*,*,#306,.F.);
#731=ORIENTED_EDGE('',*,*,#705,.T.);
#732=DIRECTION('',(0.,0.,1.));
#733=VECTOR('',#732,1.);
#734=CARTESIAN_POINT('',(1.2065,0.248,0.790460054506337));
#735=LINE('',#734,#733);
#736=CARTESIAN_POINT('',(1.2065,0.248,1.05018449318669));
#737=VERTEX_POINT('',#736);
#738=EDGE_CURVE('E376',#704,#737,#735,.T.);
#739=ORIENTED_EDGE('',*,*,#738,.T.);
#740=DIRECTION('',(0.,-0.98880509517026,0.149212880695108));
#741=VECTOR('',#740,1.);
#742=CARTESIAN_POINT('',(1.2065,0.248,1.05018449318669));
#743=LINE('',#742,#741);
#744=CARTESIAN_POINT('',(1.2065,-0.295933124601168,1.13226520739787));
#745=VERTEX_POINT('',#744);
#746=EDGE_CURVE('E379',#737,#745,#743,.T.);
#747=ORIENTED_EDGE('',*,*,#746,.T.);
#748=DIRECTION('',(0.,-0.0690684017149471,0.997611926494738));
#749=VECTOR('',#748,1.);
#750=CARTESIAN_POINT('',(1.2065,-0.295933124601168,1.13226520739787));
#751=LINE('',#750,#749);
#752=CARTESIAN_POINT('',(1.2065,-0.315447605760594,1.41412896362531));
#753=VERTEX_POINT('',#752);
#754=EDGE_CURVE('E382',#745,#753,#751,.T.);
#755=ORIENTED_EDGE('',*,*,#754,.T.);
#756=DIRECTION('',(0.,-0.997611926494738,-0.0690684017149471));
#757=VECTOR('',#756,1.);
#758=CARTESIAN_POINT('',(1.2065,-0.315447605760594,1.41412896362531));
#759=LINE('',#758,#757);
#760=CARTESIAN_POINT('',(1.2065,-0.562855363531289,1.397));
#761=VERTEX_POINT('',#760);
#762=EDGE_CURVE('E384',#753,#761,#759,.T.);
#763=ORIENTED_EDGE('',*,*,#762,.T.);
#764=DIRECTION('',(0.,0.0690684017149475,-0.997611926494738));
#765=VECTOR('',#764,1.);
#766=CARTESIAN_POINT('',(1.2065,-0.529179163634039,0.910586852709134));
#767=LINE('',#766,#765);
#768=CARTESIAN_POINT('',(1.2065,-0.529179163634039,0.910586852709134));
#769=VERTEX_POINT('',#768);
#770=EDGE_CURVE('E386',#761,#769,#767,.T.);
#771=ORIENTED_EDGE('',*,*,#770,.T.);
#772=DIRECTION('',(0.,0.98880509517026,-0.149212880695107));
#773=VECTOR('',#772,1.);
#774=CARTESIAN_POINT('',(1.2065,0.,0.830732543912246));
#775=LINE('',#774,#773);
#776=EDGE_CURVE('E388',#769,#682,#775,.T.);
#777=ORIENTED_EDGE('',*,*,#776,.T.);
#778=ORIENTED_EDGE('',*,*,#683,.T.);
#779=EDGE_LOOP('',(#730,#731,#739,#747,#755,#763,#771,#777,#778));
#780=FACE_BOUND('',#779,.T.);
#781=ADVANCED_FACE('F615',(#780),#729,.T.);
#782=CARTESIAN_POINT('',(0.6985,0.248,0.790460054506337));
#783=DIRECTION('',(1.,0.,0.));
#784=DIRECTION('',(0.,0.,-1.));
#785=AXIS2_PLACEMENT_3D('',#782,#783,#784);
#786=PLANE('',#785);
#787=ORIENTED_EDGE('',*,*,#714,.F.);
#788=ORIENTED_EDGE('',*,*,#292,.T.);
#789=ORIENTED_EDGE('',*,*,#674,.F.);
#790=DIRECTION('',(0.,0.98880509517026,-0.149212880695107));
#791=VECTOR('',#790,1.);
#792=CARTESIAN_POINT('',(0.6985,0.,0.830732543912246));
#793=LINE('',#792,#791);
#794=CARTESIAN_POINT('',(0.6985,-0.529179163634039,0.910586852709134));
#795=VERTEX_POINT('',#794);
#796=EDGE_CURVE('E406',#795,#673,#793,.T.);
#797=ORIENTED_EDGE('',*,*,#796,.F.);
#798=DIRECTION('',(0.,0.0690684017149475,-0.997611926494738));
#799=VECTOR('',#798,1.);
#800=CARTESIAN_POINT('',(0.6985,-0.529179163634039,0.910586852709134));
#801=LINE('',#800,#799);
#802=CARTESIAN_POINT('',(0.6985,-0.562855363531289,1.397));
#803=VERTEX_POINT('',#802);
#804=EDGE_CURVE('E404',#803,#795,#801,.T.);
#805=ORIENTED_EDGE('',*,*,#804,.F.);
#806=DIRECTION('',(0.,-0.997611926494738,-0.0690684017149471));
#807=VECTOR('',#806,1.);
#808=CARTESIAN_POINT('',(0.6985,-0.315447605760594,1.41412896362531));
#809=LINE('',#808,#807);
#810=CARTESIAN_POINT('',(0.6985,-0.315447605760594,1.41412896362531));
#811=VERTEX_POINT('',#810);
#812=EDGE_CURVE('E402',#811,#803,#809,.T.);
#813=ORIENTED_EDGE('',*,*,#812,.F.);
#814=DIRECTION('',(0.,-0.0690684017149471,0.997611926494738));
#815=VECTOR('',#814,1.);
#816=CARTESIAN_POINT('',(0.6985,-0.295933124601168,1.13226520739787));
#817=LINE('',#816,#815);
#818=CARTESIAN_POINT('',(0.6985,-0.295933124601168,1.13226520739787));
#819=VERTEX_POINT('',#818);
#820=EDGE_CURVE('E400',#819,#811,#817,.T.);
#821=ORIENTED_EDGE('',*,*,#820,.F.);
#822=DIRECTION('',(0.,-0.98880509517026,0.149212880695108));
#823=VECTOR('',#822,1.);
#824=CARTESIAN_POINT('',(0.6985,0.248,1.05018449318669));
#825=LINE('',#824,#823);
#826=CARTESIAN_POINT('',(0.6985,0.248,1.05018449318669));
#827=VERTEX_POINT('',#826);
#828=EDGE_CURVE('E398',#827,#819,#825,.T.);
#829=ORIENTED_EDGE('',*,*,#828,.F.);
#830=DIRECTION('',(0.,0.,1.));
#831=VECTOR('',#830,1.);
#832=CARTESIAN_POINT('',(0.6985,0.248,0.790460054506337));
#833=LINE('',#832,#831);
#834=EDGE_CURVE('E363',#713,#827,#833,.T.);
#835=ORIENTED_EDGE('',*,*,#834,.F.);
#836=EDGE_LOOP('',(#787,#788,#789,#797,#805,#813,#821,#829,#835));
#837=FACE_BOUND('',#836,.T.);
#838=ADVANCED_FACE('F626',(#837),#786,.F.);
#839=CARTESIAN_POINT('',(1.2065,0.248,0.790460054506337));
#840=DIRECTION('',(0.,-1.,0.));
#841=DIRECTION('',(0.,0.,-1.));
#842=AXIS2_PLACEMENT_3D('',#839,#840,#841);
#843=PLANE('',#842);
#844=ORIENTED_EDGE('',*,*,#834,.T.);
#845=DIRECTION('',(-1.,0.,0.));
#846=VECTOR('',#845,1.);
#847=CARTESIAN_POINT('',(1.2065,0.248,1.05018449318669));
#848=LINE('',#847,#846);
#849=EDGE_CURVE('E429',#737,#827,#848,.T.);
#850=ORIENTED_EDGE('',*,*,#849,.F.);
#851=ORIENTED_EDGE('',*,*,#738,.F.);
#852=ORIENTED_EDGE('',*,*,#720,.T.);
#853=EDGE_LOOP('',(#844,#850,#851,#852));
#854=FACE_BOUND('',#853,.T.);
#855=ADVANCED_FACE('F636',(#854),#843,.F.);
#856=CARTESIAN_POINT('',(1.2065,0.248,1.05018449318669));
#857=DIRECTION('',(0.,-0.149212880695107,-0.98880509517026));
#858=DIRECTION('',(0.,0.98880509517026,-0.149212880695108));
#859=AXIS2_PLACEMENT_3D('',#856,#857,#858);
#860=PLANE('',#859);
#861=ORIENTED_EDGE('',*,*,#828,.T.);
#862=DIRECTION('',(-1.,0.,0.));
#863=VECTOR('',#862,1.);
#864=CARTESIAN_POINT('',(1.2065,-0.295933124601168,1.13226520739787));
#865=LINE('',#864,#863);
#866=EDGE_CURVE('E426',#745,#819,#865,.T.);
#867=ORIENTED_EDGE('',*,*,#866,.F.);
#868=ORIENTED_EDGE('',*,*,#746,.F.);
#869=ORIENTED_EDGE('',*,*,#849,.T.);
#870=EDGE_LOOP('',(#861,#867,#868,#869));
#871=FACE_BOUND('',#870,.T.);
#872=ADVANCED_FACE('F638',(#871),#860,.F.);
#873=CARTESIAN_POINT('',(1.2065,-0.295933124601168,1.13226520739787));
#874=DIRECTION('',(0.,-0.997611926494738,-0.0690684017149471));
#875=DIRECTION('',(0.,0.0690684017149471,-0.997611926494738));
#876=AXIS2_PLACEMENT_3D('',#873,#874,#875);
#877=PLANE('',#876);
#878=ORIENTED_EDGE('',*,*,#820,.T.);
#879=DIRECTION('',(-1.,0.,0.));
#880=VECTOR('',#879,1.);
#881=CARTESIAN_POINT('',(1.2065,-0.315447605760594,1.41412896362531));
#882=LINE('',#881,#880);
#883=EDGE_CURVE('E423',#753,#811,#882,.T.);
#884=ORIENTED_EDGE('',*,*,#883,.F.);
#885=ORIENTED_EDGE('',*,*,#754,.F.);
#886=ORIENTED_EDGE('',*,*,#866,.T.);
#887=EDGE_LOOP('',(#878,#884,#885,#886));
#888=FACE_BOUND('',#887,.T.);
#889=ADVANCED_FACE('F643',(#888),#877,.F.);
#890=CARTESIAN_POINT('',(1.2065,-0.315447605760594,1.41412896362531));
#891=DIRECTION('',(0.,0.0690684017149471,-0.997611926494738));
#892=DIRECTION('',(0.,0.997611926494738,0.0690684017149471));
#893=AXIS2_PLACEMENT_3D('',#890,#891,#892);
#894=PLANE('',#893);
#895=ORIENTED_EDGE('',*,*,#812,.T.);
#896=DIRECTION('',(-1.,0.,0.));
#897=VECTOR('',#896,1.);
#898=CARTESIAN_POINT('',(1.2065,-0.562855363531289,1.397));
#899=LINE('',#898,#897);
#900=EDGE_CURVE('E420',#761,#803,#899,.T.);
#901=ORIENTED_EDGE('',*,*,#900,.F.);
#902=ORIENTED_EDGE('',*,*,#762,.F.);
#903=ORIENTED_EDGE('',*,*,#883,.T.);
#904=EDGE_LOOP('',(#895,#901,#902,#903));
#905=FACE_BOUND('',#904,.T.);
#906=ADVANCED_FACE('F647',(#905),#894,.F.);
#907=CARTESIAN_POINT('',(1.2065,-0.529179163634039,0.910586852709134));
#908=DIRECTION('',(0.,0.997611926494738,0.0690684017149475));
#909=DIRECTION('',(0.,-0.0690684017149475,0.997611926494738));
#910=AXIS2_PLACEMENT_3D('',#907,#908,#909);
#911=PLANE('',#910);
#912=ORIENTED_EDGE('',*,*,#804,.T.);
#913=DIRECTION('',(-1.,0.,0.));
#914=VECTOR('',#913,1.);
#915=CARTESIAN_POINT('',(1.2065,-0.529179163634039,0.910586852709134));
#916=LINE('',#915,#914);
#917=EDGE_CURVE('E417',#769,#795,#916,.T.);
#918=ORIENTED_EDGE('',*,*,#917,.F.);
#919=ORIENTED_EDGE('',*,*,#770,.F.);
#920=ORIENTED_EDGE('',*,*,#900,.T.);
#921=EDGE_LOOP('',(#912,#918,#919,#920));
#922=FACE_BOUND('',#921,.T.);
#923=ADVANCED_FACE('F650',(#922),#911,.F.);
#924=CARTESIAN_POINT('',(1.2065,0.,0.830732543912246));
#925=DIRECTION('',(0.,0.149212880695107,0.98880509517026));
#926=DIRECTION('',(0.,-0.98880509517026,0.149212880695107));
#927=AXIS2_PLACEMENT_3D('',#924,#925,#926);
#928=PLANE('',#927);
#929=ORIENTED_EDGE('',*,*,#796,.T.);
#930=ORIENTED_EDGE('',*,*,#689,.F.);
#931=ORIENTED_EDGE('',*,*,#776,.F.);
#932=ORIENTED_EDGE('',*,*,#917,.T.);
#933=EDGE_LOOP('',(#929,#930,#931,#932));
#934=FACE_BOUND('',#933,.T.);
#935=ADVANCED_FACE('F622',(#934),#928,.F.);
#936=CARTESIAN_POINT('',(-1.2065,0.248,0.790460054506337));
#937=DIRECTION('',(0.,0.,-1.));
#938=DIRECTION('',(-1.,0.,0.));
#939=AXIS2_PLACEMENT_3D('',#936,#937,#938);
#940=PLANE('',#939);
#941=ORIENTED_EDGE('',*,*,#277,.F.);
#942=DIRECTION('',(0.,1.,0.));
#943=VECTOR('',#942,1.);
#944=CARTESIAN_POINT('',(-1.2065,0.248,0.790460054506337));
#945=LINE('',#944,#943);
#946=CARTESIAN_POINT('',(-1.2065,0.248,0.790460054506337));
#947=VERTEX_POINT('',#946);
#948=EDGE_CURVE('E315',#268,#947,#945,.T.);
#949=ORIENTED_EDGE('',*,*,#948,.T.);
#950=DIRECTION('',(1.,0.,0.));
#951=VECTOR('',#950,1.);
#952=CARTESIAN_POINT('',(-1.2065,0.248,0.790460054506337));
#953=LINE('',#952,#951);
#954=CARTESIAN_POINT('',(-0.6985,0.248,0.790460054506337));
#955=VERTEX_POINT('',#954);
#956=EDGE_CURVE('E339',#947,#955,#953,.T.);
#957=ORIENTED_EDGE('',*,*,#956,.T.);
#958=DIRECTION('',(0.,1.,0.));
#959=VECTOR('',#958,1.);
#960=CARTESIAN_POINT('',(-0.6985,0.248,0.790460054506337));
#961=LINE('',#960,#959);
#962=EDGE_CURVE('E311',#276,#955,#961,.T.);
#963=ORIENTED_EDGE('',*,*,#962,.F.);
#964=EDGE_LOOP('',(#941,#949,#957,#963));
#965=FACE_BOUND('',#964,.T.);
#966=ADVANCED_FACE('F573',(#965),#940,.T.);
#967=CARTESIAN_POINT('',(-1.2065,0.,0.790460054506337));
#968=DIRECTION('',(0.,-1.,0.));
#969=DIRECTION('',(0.,0.,-1.));
#970=AXIS2_PLACEMENT_3D('',#967,#968,#969);
#971=PLANE('',#970);
#972=ORIENTED_EDGE('',*,*,#162,.T.);
#973=DIRECTION('',(0.,0.,-1.));
#974=VECTOR('',#973,1.);
#975=CARTESIAN_POINT('',(-0.6985,0.,0.790460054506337));
#976=LINE('',#975,#974);
#977=CARTESIAN_POINT('',(-0.6985,0.,0.830732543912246));
#978=VERTEX_POINT('',#977);
#979=EDGE_CURVE('E318',#978,#159,#976,.T.);
#980=ORIENTED_EDGE('',*,*,#979,.F.);
#981=DIRECTION('',(1.,0.,0.));
#982=VECTOR('',#981,1.);
#983=CARTESIAN_POINT('',(-1.2065,0.,0.830732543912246));
#984=LINE('',#983,#982);
#985=CARTESIAN_POINT('',(-1.2065,0.,0.830732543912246));
#986=VERTEX_POINT('',#985);
#987=EDGE_CURVE('E361',#986,#978,#984,.T.);
#988=ORIENTED_EDGE('',*,*,#987,.F.);
#989=DIRECTION('',(0.,0.,-1.));
#990=VECTOR('',#989,1.);
#991=CARTESIAN_POINT('',(-1.2065,0.,0.790460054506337));
#992=LINE('',#991,#990);
#993=EDGE_CURVE('E336',#986,#139,#992,.T.);
#994=ORIENTED_EDGE('',*,*,#993,.T.);
#995=EDGE_LOOP('',(#972,#980,#988,#994));
#996=FACE_BOUND('',#995,.T.);
#997=ADVANCED_FACE('F602',(#996),#971,.T.);
#998=CARTESIAN_POINT('',(-1.2065,0.,0.790460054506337));
#999=DIRECTION('',(-1.,0.,0.));
#1000=DIRECTION('',(0.,0.,1.));
#1001=AXIS2_PLACEMENT_3D('',#998,#999,#1000);
#1002=PLANE('',#1001);
#1003=ORIENTED_EDGE('',*,*,#269,.F.);
#1004=ORIENTED_EDGE('',*,*,#993,.F.);
#1005=DIRECTION('',(0.,0.98880509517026,-0.149212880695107));
#1006=VECTOR('',#1005,1.);
#1007=CARTESIAN_POINT('',(-1.2065,0.,0.830732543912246));
#1008=LINE('',#1007,#1006);
#1009=CARTESIAN_POINT('',(-1.2065,-0.529179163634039,0.910586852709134));
#1010=VERTEX_POINT('',#1009);
#1011=EDGE_CURVE('E333',#1010,#986,#1008,.T.);
#1012=ORIENTED_EDGE('',*,*,#1011,.F.);
#1013=DIRECTION('',(0.,0.0690684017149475,-0.997611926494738));
#1014=VECTOR('',#1013,1.);
#1015=CARTESIAN_POINT('',(-1.2065,-0.529179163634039,0.910586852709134));
#1016=LINE('',#1015,#1014);
#1017=CARTESIAN_POINT('',(-1.2065,-0.562855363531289,1.397));
#1018=VERTEX_POINT('',#1017);
#1019=EDGE_CURVE('E330',#1018,#1010,#1016,.T.);
#1020=ORIENTED_EDGE('',*,*,#1019,.F.);
#1021=DIRECTION('',(0.,-0.997611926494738,-0.0690684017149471));
#1022=VECTOR('',#1021,1.);
#1023=CARTESIAN_POINT('',(-1.2065,-0.315447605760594,1.41412896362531));
#1024=LINE('',#1023,#1022);
#1025=CARTESIAN_POINT('',(-1.2065,-0.315447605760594,1.41412896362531));
#1026=VERTEX_POINT('',#1025);
#1027=EDGE_CURVE('E327',#1026,#1018,#1024,.T.);
#1028=ORIENTED_EDGE('',*,*,#1027,.F.);
#1029=DIRECTION('',(0.,-0.0690684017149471,0.997611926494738));
#1030=VECTOR('',#1029,1.);
#1031=CARTESIAN_POINT('',(-1.2065,-0.295933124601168,1.13226520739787));
#1032=LINE('',#1031,#1030);
#1033=CARTESIAN_POINT('',(-1.2065,-0.295933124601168,1.13226520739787));
#1034=VERTEX_POINT('',#1033);
#1035=EDGE_CURVE('E324',#1034,#1026,#1032,.T.);
#1036=ORIENTED_EDGE('',*,*,#1035,.F.);
#1037=DIRECTION('',(0.,-0.98880509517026,0.149212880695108));
#1038=VECTOR('',#1037,1.);
#1039=CARTESIAN_POINT('',(-1.2065,0.248,1.05018449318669));
#1040=LINE('',#1039,#1038);
#1041=CARTESIAN_POINT('',(-1.2065,0.248,1.05018449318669));
#1042=VERTEX_POINT('',#1041);
#1043=EDGE_CURVE('E321',#1042,#1034,#1040,.T.);
#1044=ORIENTED_EDGE('',*,*,#1043,.F.);
#1045=DIRECTION('',(0.,0.,1.));
#1046=VECTOR('',#1045,1.);
#1047=CARTESIAN_POINT('',(-1.2065,0.248,0.790460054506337));
#1048=LINE('',#1047,#1046);
#1049=EDGE_CURVE('E317',#947,#1042,#1048,.T.);
#1050=ORIENTED_EDGE('',*,*,#1049,.F.);
#1051=ORIENTED_EDGE('',*,*,#948,.F.);
#1052=EDGE_LOOP('',(#1003,#1004,#1012,#1020,#1028,#1036,#1044,#1050,#1051));
#1053=FACE_BOUND('',#1052,.T.);
#1054=ADVANCED_FACE('F700',(#1053),#1002,.T.);
#1055=CARTESIAN_POINT('',(-0.6985,0.,0.790460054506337));
#1056=DIRECTION('',(-1.,0.,0.));
#1057=DIRECTION('',(0.,0.,1.));
#1058=AXIS2_PLACEMENT_3D('',#1055,#1056,#1057);
#1059=PLANE('',#1058);
#1060=ORIENTED_EDGE('',*,*,#979,.T.);
#1061=ORIENTED_EDGE('',*,*,#283,.T.);
#1062=ORIENTED_EDGE('',*,*,#962,.T.);
#1063=DIRECTION('',(0.,0.,1.));
#1064=VECTOR('',#1063,1.);
#1065=CARTESIAN_POINT('',(-0.6985,0.248,0.790460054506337));
#1066=LINE('',#1065,#1064);
#1067=CARTESIAN_POINT('',(-0.6985,0.248,1.05018449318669));
#1068=VERTEX_POINT('',#1067);
#1069=EDGE_CURVE('E341',#955,#1068,#1066,.T.);
#1070=ORIENTED_EDGE('',*,*,#1069,.T.);
#1071=DIRECTION('',(0.,-0.98880509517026,0.149212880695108));
#1072=VECTOR('',#1071,1.);
#1073=CARTESIAN_POINT('',(-0.6985,0.248,1.05018449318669));
#1074=LINE('',#1073,#1072);
#1075=CARTESIAN_POINT('',(-0.6985,-0.295933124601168,1.13226520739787));
#1076=VERTEX_POINT('',#1075);
#1077=EDGE_CURVE('E344',#1068,#1076,#1074,.T.);
#1078=ORIENTED_EDGE('',*,*,#1077,.T.);
#1079=DIRECTION('',(0.,-0.0690684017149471,0.997611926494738));
#1080=VECTOR('',#1079,1.);
#1081=CARTESIAN_POINT('',(-0.6985,-0.295933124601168,1.13226520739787));
#1082=LINE('',#1081,#1080);
#1083=CARTESIAN_POINT('',(-0.6985,-0.315447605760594,1.41412896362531));
#1084=VERTEX_POINT('',#1083);
#1085=EDGE_CURVE('E347',#1076,#1084,#1082,.T.);
#1086=ORIENTED_EDGE('',*,*,#1085,.T.);
#1087=DIRECTION('',(0.,-0.997611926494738,-0.0690684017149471));
#1088=VECTOR('',#1087,1.);
#1089=CARTESIAN_POINT('',(-0.6985,-0.315447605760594,1.41412896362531));
#1090=LINE('',#1089,#1088);
#1091=CARTESIAN_POINT('',(-0.6985,-0.562855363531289,1.397));
#1092=VERTEX_POINT('',#1091);
#1093=EDGE_CURVE('E350',#1084,#1092,#1090,.T.);
#1094=ORIENTED_EDGE('',*,*,#1093,.T.);
#1095=DIRECTION('',(0.,0.0690684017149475,-0.997611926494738));
#1096=VECTOR('',#1095,1.);
#1097=CARTESIAN_POINT('',(-0.6985,-0.529179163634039,0.910586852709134));
#1098=LINE('',#1097,#1096);
#1099=CARTESIAN_POINT('',(-0.6985,-0.529179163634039,0.910586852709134));
#1100=VERTEX_POINT('',#1099);
#1101=EDGE_CURVE('E353',#1092,#1100,#1098,.T.);
#1102=ORIENTED_EDGE('',*,*,#1101,.T.);
#1103=DIRECTION('',(0.,0.98880509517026,-0.149212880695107));
#1104=VECTOR('',#1103,1.);
#1105=CARTESIAN_POINT('',(-0.6985,0.,0.830732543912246));
#1106=LINE('',#1105,#1104);
#1107=EDGE_CURVE('E356',#1100,#978,#1106,.T.);
#1108=ORIENTED_EDGE('',*,*,#1107,.T.);
#1109=EDGE_LOOP('',(#1060,#1061,#1062,#1070,#1078,#1086,#1094,#1102,#1108));
#1110=FACE_BOUND('',#1109,.T.);
#1111=ADVANCED_FACE('F571',(#1110),#1059,.F.);
#1112=CARTESIAN_POINT('',(-1.2065,0.,0.830732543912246));
#1113=DIRECTION('',(0.,-0.149212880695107,-0.98880509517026));
#1114=DIRECTION('',(0.,0.98880509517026,-0.149212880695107));
#1115=AXIS2_PLACEMENT_3D('',#1112,#1113,#1114);
#1116=PLANE('',#1115);
#1117=ORIENTED_EDGE('',*,*,#1107,.F.);
#1118=DIRECTION('',(1.,0.,0.));
#1119=VECTOR('',#1118,1.);
#1120=CARTESIAN_POINT('',(-1.2065,-0.529179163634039,0.910586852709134));
#1121=LINE('',#1120,#1119);
#1122=EDGE_CURVE('E364',#1010,#1100,#1121,.T.);
#1123=ORIENTED_EDGE('',*,*,#1122,.F.);
#1124=ORIENTED_EDGE('',*,*,#1011,.T.);
#1125=ORIENTED_EDGE('',*,*,#987,.T.);
#1126=EDGE_LOOP('',(#1117,#1123,#1124,#1125));
#1127=FACE_BOUND('',#1126,.T.);
#1128=ADVANCED_FACE('F598',(#1127),#1116,.T.);
#1129=CARTESIAN_POINT('',(-1.2065,-0.529179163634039,0.910586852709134));
#1130=DIRECTION('',(0.,-0.997611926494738,-0.0690684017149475));
#1131=DIRECTION('',(0.,0.0690684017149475,-0.997611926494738));
#1132=AXIS2_PLACEMENT_3D('',#1129,#1130,#1131);
#1133=PLANE('',#1132);
#1134=ORIENTED_EDGE('',*,*,#1101,.F.);
#1135=DIRECTION('',(1.,0.,0.));
#1136=VECTOR('',#1135,1.);
#1137=CARTESIAN_POINT('',(-1.2065,-0.562855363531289,1.397));
#1138=LINE('',#1137,#1136);
#1139=EDGE_CURVE('E366',#1018,#1092,#1138,.T.);
#1140=ORIENTED_EDGE('',*,*,#1139,.F.);
#1141=ORIENTED_EDGE('',*,*,#1019,.T.);
#1142=ORIENTED_EDGE('',*,*,#1122,.T.);
#1143=EDGE_LOOP('',(#1134,#1140,#1141,#1142));
#1144=FACE_BOUND('',#1143,.T.);
#1145=ADVANCED_FACE('F594',(#1144),#1133,.T.);
#1146=CARTESIAN_POINT('',(-1.2065,-0.315447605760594,1.41412896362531));
#1147=DIRECTION('',(0.,-0.0690684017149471,0.997611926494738));
#1148=DIRECTION('',(0.,-0.997611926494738,-0.0690684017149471));
#1149=AXIS2_PLACEMENT_3D('',#1146,#1147,#1148);
#1150=PLANE('',#1149);
#1151=ORIENTED_EDGE('',*,*,#1093,.F.);
#1152=DIRECTION('',(1.,0.,0.));
#1153=VECTOR('',#1152,1.);
#1154=CARTESIAN_POINT('',(-1.2065,-0.315447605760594,1.41412896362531));
#1155=LINE('',#1154,#1153);
#1156=EDGE_CURVE('E368',#1026,#1084,#1155,.T.);
#1157=ORIENTED_EDGE('',*,*,#1156,.F.);
#1158=ORIENTED_EDGE('',*,*,#1027,.T.);
#1159=ORIENTED_EDGE('',*,*,#1139,.T.);
#1160=EDGE_LOOP('',(#1151,#1157,#1158,#1159));
#1161=FACE_BOUND('',#1160,.T.);
#1162=ADVANCED_FACE('F590',(#1161),#1150,.T.);
#1163=CARTESIAN_POINT('',(-1.2065,-0.295933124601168,1.13226520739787));
#1164=DIRECTION('',(0.,0.997611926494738,0.0690684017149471));
#1165=DIRECTION('',(0.,-0.0690684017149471,0.997611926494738));
#1166=AXIS2_PLACEMENT_3D('',#1163,#1164,#1165);
#1167=PLANE('',#1166);
#1168=ORIENTED_EDGE('',*,*,#1085,.F.);
#1169=DIRECTION('',(1.,0.,0.));
#1170=VECTOR('',#1169,1.);
#1171=CARTESIAN_POINT('',(-1.2065,-0.295933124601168,1.13226520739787));
#1172=LINE('',#1171,#1170);
#1173=EDGE_CURVE('E370',#1034,#1076,#1172,.T.);
#1174=ORIENTED_EDGE('',*,*,#1173,.F.);
#1175=ORIENTED_EDGE('',*,*,#1035,.T.);
#1176=ORIENTED_EDGE('',*,*,#1156,.T.);
#1177=EDGE_LOOP('',(#1168,#1174,#1175,#1176));
#1178=FACE_BOUND('',#1177,.T.);
#1179=ADVANCED_FACE('F586',(#1178),#1167,.T.);
#1180=CARTESIAN_POINT('',(-1.2065,0.248,1.05018449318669));
#1181=DIRECTION('',(0.,0.149212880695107,0.98880509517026));
#1182=DIRECTION('',(0.,-0.98880509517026,0.149212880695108));
#1183=AXIS2_PLACEMENT_3D('',#1180,#1181,#1182);
#1184=PLANE('',#1183);
#1185=ORIENTED_EDGE('',*,*,#1077,.F.);
#1186=DIRECTION('',(1.,0.,0.));
#1187=VECTOR('',#1186,1.);
#1188=CARTESIAN_POINT('',(-1.2065,0.248,1.05018449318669));
#1189=LINE('',#1188,#1187);
#1190=EDGE_CURVE('E372',#1042,#1068,#1189,.T.);
#1191=ORIENTED_EDGE('',*,*,#1190,.F.);
#1192=ORIENTED_EDGE('',*,*,#1043,.T.);
#1193=ORIENTED_EDGE('',*,*,#1173,.T.);
#1194=EDGE_LOOP('',(#1185,#1191,#1192,#1193));
#1195=FACE_BOUND('',#1194,.T.);
#1196=ADVANCED_FACE('F582',(#1195),#1184,.T.);
#1197=CARTESIAN_POINT('',(-1.2065,0.248,0.790460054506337));
#1198=DIRECTION('',(0.,1.,0.));
#1199=DIRECTION('',(0.,0.,1.));
#1200=AXIS2_PLACEMENT_3D('',#1197,#1198,#1199);
#1201=PLANE('',#1200);
#1202=ORIENTED_EDGE('',*,*,#1069,.F.);
#1203=ORIENTED_EDGE('',*,*,#956,.F.);
#1204=ORIENTED_EDGE('',*,*,#1049,.T.);
#1205=ORIENTED_EDGE('',*,*,#1190,.T.);
#1206=EDGE_LOOP('',(#1202,#1203,#1204,#1205));
#1207=FACE_BOUND('',#1206,.T.);
#1208=ADVANCED_FACE('F578',(#1207),#1201,.T.);
#1209=CARTESIAN_POINT('',(-0.0446511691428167,-0.0920000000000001,-0.0437209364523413));
#1210=DIRECTION('',(-1.,0.,0.));
#1211=DIRECTION('',(0.,0.,1.));
#1212=AXIS2_PLACEMENT_3D('',#1209,#1210,#1211);
#1213=PLANE('',#1212);
#1214=ORIENTED_EDGE('',*,*,#357,.T.);
#1215=DIRECTION('',(0.,1.,0.));
#1216=VECTOR('',#1215,1.);
#1217=CARTESIAN_POINT('',(-0.0446511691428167,-0.0920000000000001,0.0437209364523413));
#1218=LINE('',#1217,#1216);
#1219=CARTESIAN_POINT('',(-0.0446511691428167,-0.0920000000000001,0.0437209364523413));
#1220=VERTEX_POINT('',#1219);
#1221=EDGE_CURVE('E274',#1220,#356,#1218,.T.);
#1222=ORIENTED_EDGE('',*,*,#1221,.F.);
#1223=DIRECTION('',(0.,0.,1.));
#1224=VECTOR('',#1223,1.);
#1225=CARTESIAN_POINT('',(-0.0446511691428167,-0.0920000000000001,-0.0437209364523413));
#1226=LINE('',#1225,#1224);
#1227=CARTESIAN_POINT('',(-0.0446511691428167,-0.0920000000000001,-0.0437209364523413));
#1228=VERTEX_POINT('',#1227);
#1229=EDGE_CURVE('E278',#1228,#1220,#1226,.T.);
#1230=ORIENTED_EDGE('',*,*,#1229,.F.);
#1231=DIRECTION('',(0.,1.,0.));
#1232=VECTOR('',#1231,1.);
#1233=CARTESIAN_POINT('',(-0.0446511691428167,-0.0920000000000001,-0.0437209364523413));
#1234=LINE('',#1233,#1232);
#1235=EDGE_CURVE('E309',#1228,#354,#1234,.T.);
#1236=ORIENTED_EDGE('',*,*,#1235,.T.);
#1237=EDGE_LOOP('',(#1214,#1222,#1230,#1236));
#1238=FACE_BOUND('',#1237,.T.);
#1239=ADVANCED_FACE('F276',(#1238),#1213,.F.);
#1240=CARTESIAN_POINT('',(-0.0446511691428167,-0.0920000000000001,-0.0437209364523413));
#1241=DIRECTION('',(0.,0.,-1.));
#1242=DIRECTION('',(-1.,0.,0.));
#1243=AXIS2_PLACEMENT_3D('',#1240,#1241,#1242);
#1244=PLANE('',#1243);
#1245=ORIENTED_EDGE('',*,*,#365,.T.);
#1246=ORIENTED_EDGE('',*,*,#1235,.F.);
#1247=DIRECTION('',(-1.,0.,0.));
#1248=VECTOR('',#1247,1.);
#1249=CARTESIAN_POINT('',(-0.0446511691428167,-0.0920000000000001,-0.0437209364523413));
#1250=LINE('',#1249,#1248);
#1251=CARTESIAN_POINT('',(0.0446511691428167,-0.0920000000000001,-0.0437209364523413));
#1252=VERTEX_POINT('',#1251);
#1253=EDGE_CURVE('E284',#1252,#1228,#1250,.T.);
#1254=ORIENTED_EDGE('',*,*,#1253,.F.);
#1255=DIRECTION('',(0.,1.,0.));
#1256=VECTOR('',#1255,1.);
#1257=CARTESIAN_POINT('',(0.0446511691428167,-0.0920000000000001,-0.0437209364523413));
#1258=LINE('',#1257,#1256);
#1259=EDGE_CURVE('E312',#1252,#364,#1258,.T.);
#1260=ORIENTED_EDGE('',*,*,#1259,.T.);
#1261=EDGE_LOOP('',(#1245,#1246,#1254,#1260));
#1262=FACE_BOUND('',#1261,.T.);
#1263=ADVANCED_FACE('F1027',(#1262),#1244,.F.);
#1264=CARTESIAN_POINT('',(0.0446511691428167,-0.0920000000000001,-0.0437209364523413));
#1265=DIRECTION('',(1.,0.,0.));
#1266=DIRECTION('',(0.,0.,-1.));
#1267=AXIS2_PLACEMENT_3D('',#1264,#1265,#1266);
#1268=PLANE('',#1267);
#1269=ORIENTED_EDGE('',*,*,#373,.T.);
#1270=ORIENTED_EDGE('',*,*,#1259,.F.);
#1271=DIRECTION('',(0.,0.,-1.));
#1272=VECTOR('',#1271,1.);
#1273=CARTESIAN_POINT('',(0.0446511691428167,-0.0920000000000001,-0.0437209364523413));
#1274=LINE('',#1273,#1272);
#1275=CARTESIAN_POINT('',(0.0446511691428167,-0.0920000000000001,0.0437209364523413));
#1276=VERTEX_POINT('',#1275);
#1277=EDGE_CURVE('E292',#1276,#1252,#1274,.T.);
#1278=ORIENTED_EDGE('',*,*,#1277,.F.);
#1279=DIRECTION('',(0.,1.,0.));
#1280=VECTOR('',#1279,1.);
#1281=CARTESIAN_POINT('',(0.0446511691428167,-0.0920000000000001,0.0437209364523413));
#1282=LINE('',#1281,#1280);
#1283=EDGE_CURVE('E283',#1276,#372,#1282,.T.);
#1284=ORIENTED_EDGE('',*,*,#1283,.T.);
#1285=EDGE_LOOP('',(#1269,#1270,#1278,#1284));
#1286=FACE_BOUND('',#1285,.T.);
#1287=ADVANCED_FACE('F1032',(#1286),#1268,.F.);
#1288=CARTESIAN_POINT('',(-0.0446511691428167,-0.0920000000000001,0.0437209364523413));
#1289=DIRECTION('',(0.,0.,1.));
#1290=DIRECTION('',(1.,0.,0.));
#1291=AXIS2_PLACEMENT_3D('',#1288,#1289,#1290);
#1292=PLANE('',#1291);
#1293=ORIENTED_EDGE('',*,*,#379,.T.);
#1294=ORIENTED_EDGE('',*,*,#1283,.F.);
#1295=DIRECTION('',(1.,0.,0.));
#1296=VECTOR('',#1295,1.);
#1297=CARTESIAN_POINT('',(-0.0446511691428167,-0.0920000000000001,0.0437209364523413));
#1298=LINE('',#1297,#1296);
#1299=EDGE_CURVE('E287',#1220,#1276,#1298,.T.);
#1300=ORIENTED_EDGE('',*,*,#1299,.F.);
#1301=ORIENTED_EDGE('',*,*,#1221,.T.);
#1302=EDGE_LOOP('',(#1293,#1294,#1300,#1301));
#1303=FACE_BOUND('',#1302,.T.);
#1304=ADVANCED_FACE('F288',(#1303),#1292,.F.);
#1305=CARTESIAN_POINT('',(-0.0446511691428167,-0.0920000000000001,0.0437209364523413));
#1306=DIRECTION('',(0.,1.,0.));
#1307=DIRECTION('',(0.,0.,1.));
#1308=AXIS2_PLACEMENT_3D('',#1305,#1306,#1307);
#1309=PLANE('',#1308);
#1310=ORIENTED_EDGE('',*,*,#1229,.T.);
#1311=ORIENTED_EDGE('',*,*,#1299,.T.);
#1312=ORIENTED_EDGE('',*,*,#1277,.T.);
#1313=ORIENTED_EDGE('',*,*,#1253,.T.);
#1314=EDGE_LOOP('',(#1310,#1311,#1312,#1313));
#1315=FACE_BOUND('',#1314,.T.);
#1316=ADVANCED_FACE('F294',(#1315),#1309,.T.);
#1317=CLOSED_SHELL('',(#58,#97,#128,#166,#178,#232,#256,#326,#343,#389,#420,#451,#508,#565,#582,
#599,#616,#633,#650,#662,#693,#724,#781,#838,#855,#872,#889,#906,#923,#935,#966,#997,#1054,
#1111,#1128,#1145,#1162,#1179,#1196,#1208,#1239,#1263,#1287,#1304,#1316));
#1318=MANIFOLD_SOLID_BREP('B2',#1317);
#1319=ADVANCED_BREP_SHAPE_REPRESENTATION('',(#18,#1318),#14);
#1320=SHAPE_DEFINITION_REPRESENTATION(#9,#1319);
ENDSEC;
END-ISO-10303-21;
